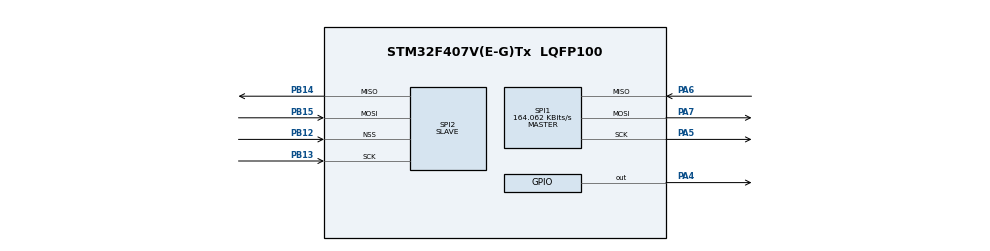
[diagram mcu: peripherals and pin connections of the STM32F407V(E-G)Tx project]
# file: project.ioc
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Mcu.Family=STM32F4
Mcu.Name=STM32F407V(E-G)Tx
Mcu.Package=LQFP100
NVIC.PriorityGroup=NVIC_PRIORITYGROUP_4
NVIC.SPI2_IRQn=true\:0\:0\:false\:false\:true\:true\:true
PA4.GPIO_Speed=GPIO_SPEED_FREQ_VERY_HIGH
PA4.PinState=GPIO_PIN_RESET
PA4.Signal=GPIO_Output
PA5.Mode=Full_Duplex_Master
PA5.Signal=SPI1_SCK
PA6.Mode=Full_Duplex_Master
PA6.Signal=SPI1_MISO
PA7.Mode=Full_Duplex_Master
PA7.Signal=SPI1_MOSI
PB12.Mode=NSS_Signal_Hard_Input
PB12.Signal=SPI2_NSS
PB13.Mode=Full_Duplex_Slave
PB13.Signal=SPI2_SCK
PB14.Mode=Full_Duplex_Slave
PB14.Signal=SPI2_MISO
PB15.Mode=Full_Duplex_Slave
PB15.Signal=SPI2_MOSI
PH0-OSC_IN.Mode=HSE-External-Oscillator
PH0-OSC_IN.Signal=RCC_OSC_IN
PH1-OSC_OUT.Mode=HSE-External-Oscillator
PH1-OSC_OUT.Signal=RCC_OSC_OUT
ProjectManager.HeapSize=0x200
ProjectManager.StackSize=0x400
ProjectManager.TargetToolchain=STM32CubeIDE
RCC.48MHZClocksFreq_Value=42000000
RCC.AHBFreq_Value=168000000
RCC.APB1CLKDivider=RCC_HCLK_DIV4
RCC.APB1Freq_Value=42000000
RCC.APB1TimFreq_Value=84000000
RCC.APB2CLKDivider=RCC_HCLK_DIV4
RCC.APB2Freq_Value=42000000
RCC.APB2TimFreq_Value=84000000
RCC.CortexFreq_Value=168000000
RCC.HCLKFreq_Value=168000000
RCC.HSE_VALUE=8000000
RCC.HSI_VALUE=16000000
RCC.LSE_VALUE=32768
RCC.PLLM=8
RCC.PLLN=336
RCC.PLLQ=8
RCC.PLLSourceVirtual=RCC_PLLSOURCE_HSE
RCC.SYSCLKFreq_VALUE=168000000
RCC.SYSCLKSource=RCC_SYSCLKSOURCE_PLLCLK
RCC.VCOOutputFreq_Value=336000000
SPI1.BaudRatePrescaler=SPI_BAUDRATEPRESCALER_256
SPI1.CRCCalculation=SPI_CRCCALCULATION_DISABLE
SPI1.CalculateBaudRate=164.062 KBits/s
SPI1.Direction=SPI_DIRECTION_2LINES
SPI1.Mode=SPI_MODE_MASTER
SPI1.VirtualType=VM_MASTER
SPI2.CRCCalculation=SPI_CRCCALCULATION_DISABLE
SPI2.Direction=SPI_DIRECTION_2LINES
SPI2.Mode=SPI_MODE_SLAVE
SPI2.VirtualNSS=VM_NSSHARD
SPI2.VirtualType=VM_SLAVE
board=project

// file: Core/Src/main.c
/**
  ******************************************************************************
  * File Name          : main.c
  * Description        : Main program body
  ******************************************************************************
  *
  * COPYRIGHT(c) 2017 STMicroelectronics
  *
  * Redistribution and use in source and binary forms, with or without modification,
  * are permitted provided that the following conditions are met:
  *   1. Redistributions of source code must retain the above copyright notice,
  *      this list of conditions and the following disclaimer.
  *   2. Redistributions in binary form must reproduce the above copyright notice,
  *      this list of conditions and the following disclaimer in the documentation
  *      and/or other materials provided with the distribution.
  *   3. Neither the name of STMicroelectronics nor the names of its contributors
  *      may be used to endorse or promote products derived from this software
  *      without specific prior written permission.
  *
  * THIS SOFTWARE IS PROVIDED BY THE COPYRIGHT HOLDERS AND CONTRIBUTORS "AS IS"
  * AND ANY EXPRESS OR IMPLIED WARRANTIES, INCLUDING, BUT NOT LIMITED TO, THE
  * IMPLIED WARRANTIES OF MERCHANTABILITY AND FITNESS FOR A PARTICULAR PURPOSE ARE
  * DISCLAIMED. IN NO EVENT SHALL THE COPYRIGHT HOLDER OR CONTRIBUTORS BE LIABLE
  * FOR ANY DIRECT, INDIRECT, INCIDENTAL, SPECIAL, EXEMPLARY, OR CONSEQUENTIAL
  * DAMAGES (INCLUDING, BUT NOT LIMITED TO, PROCUREMENT OF SUBSTITUTE GOODS OR
  * SERVICES; LOSS OF USE, DATA, OR PROFITS; OR BUSINESS INTERRUPTION) HOWEVER
  * CAUSED AND ON ANY THEORY OF LIABILITY, WHETHER IN CONTRACT, STRICT LIABILITY,
  * OR TORT (INCLUDING NEGLIGENCE OR OTHERWISE) ARISING IN ANY WAY OUT OF THE USE
  * OF THIS SOFTWARE, EVEN IF ADVISED OF THE POSSIBILITY OF SUCH DAMAGE.
  *
  ******************************************************************************
  */
#include "main.h"
#include "stm32f4xx_hal.h"

#include "DHT.h"
#include <stdio.h>

SPI_HandleTypeDef hspi1;
SPI_HandleTypeDef hspi2;

/* USER CODE BEGIN PV */
/* Private variables ---------------------------------------------------------*/
#define spi_dis HAL_GPIO_WritePin(GPIOA,GPIO_PIN_4,GPIO_PIN_SET)
#define spi_en HAL_GPIO_WritePin(GPIOA,GPIO_PIN_4,GPIO_PIN_RESET)
/* USER CODE END PV */

void SystemClock_Config(void);
void Error_Handler(void);
static void MX_GPIO_Init(void);
static void MX_SPI1_Init(void);
static void MX_SPI2_Init(void);
void Init_OnBoard_LEDs(void);

/* USER CODE BEGIN PFP */
/* Private function prototypes -----------------------------------------------*/

/* USER CODE END PFP */
uint8_t data_send = 0 , data_get;
void HAL_SPI_RxCpltCallback(SPI_HandleTypeDef *hspi);

/* USER CODE END 0 */

DHT_DataTypedef DHT11_Data;
uint8_t Temperature, Humidity;
uint8_t data2[1];
//char uart_buf[50];
//int uart_buf_len;

int main(void)
{

	//spi_dis;
  /* MCU Configuration----------------------------------------------------------*/

  /* Reset of all peripherals, Initializes the Flash interface and the Systick. */
  HAL_Init();

  /* Configure the system clock */
  SystemClock_Config();

  /* Initialize all configured peripherals */
  MX_GPIO_Init();
  MX_SPI1_Init();
  MX_SPI2_Init();

  /* USER CODE BEGIN 2 */
//HAL_SPI_Receive_IT(&hspi1, &data_get, 1);

  /* USER CODE END 2 */

Init_OnBoard_LEDs();

  /* Infinite loop */
  while (1)
  {

	  HAL_Delay(500);
	  DHT_GetData(&DHT11_Data);
	  Temperature = DHT11_Data.Temperature;
	  Humidity = DHT11_Data.Humidity;
	  /*if(Temperature > 10){
		  HAL_GPIO_TogglePin(GPIOD,GPIO_PIN_12|GPIO_PIN_13|GPIO_PIN_14|GPIO_PIN_15);
	  }*/
	  //HAL_GPIO_WritePin(GPIOD,GPIO_PIN_12|GPIO_PIN_13|GPIO_PIN_14|GPIO_PIN_15,GPIO_PIN_RESET);
	  //HAL_GPIO_TogglePin(GPIOD,GPIO_PIN_12|GPIO_PIN_13|GPIO_PIN_14|GPIO_PIN_15);
	  data_send = Temperature;
	  data2[0] = Temperature;
	  //data2[0] = 55;
	  spi_en;
	  HAL_SPI_Receive_IT(&hspi1, &data_get, 1);
	  HAL_GPIO_WritePin(GPIOD,GPIO_PIN_12|GPIO_PIN_13|GPIO_PIN_14|GPIO_PIN_15,GPIO_PIN_SET);
	  HAL_SPI_Transmit(&hspi2, data2, 1, 100000);
	  HAL_GPIO_WritePin(GPIOD,GPIO_PIN_12|GPIO_PIN_13|GPIO_PIN_14|GPIO_PIN_15,GPIO_PIN_RESET);

  }
  /* USER CODE END 3 */
}

void Init_OnBoard_LEDs(void)
{
	 __HAL_RCC_GPIOD_CLK_ENABLE();
	GPIO_InitTypeDef BoardLEDs;
	BoardLEDs.Mode = GPIO_MODE_OUTPUT_PP;
	BoardLEDs.Pin = GPIO_PIN_12|GPIO_PIN_13|GPIO_PIN_14|GPIO_PIN_15;
	HAL_GPIO_Init(GPIOD, &BoardLEDs);
}

/** System Clock Configuration
*/
void SystemClock_Config(void)
{
  RCC_OscInitTypeDef RCC_OscInitStruct = {0};
  RCC_ClkInitTypeDef RCC_ClkInitStruct = {0};

  /** Configure the main internal regulator output voltage
  */
  __HAL_RCC_PWR_CLK_ENABLE();
  __HAL_PWR_VOLTAGESCALING_CONFIG(PWR_REGULATOR_VOLTAGE_SCALE1);
  /** Initializes the RCC Oscillators according to the specified parameters
  * in the RCC_OscInitTypeDef structure.
  */
  RCC_OscInitStruct.OscillatorType = RCC_OSCILLATORTYPE_HSI;
  RCC_OscInitStruct.HSIState = RCC_HSI_ON;
  RCC_OscInitStruct.HSICalibrationValue = RCC_HSICALIBRATION_DEFAULT;
  RCC_OscInitStruct.PLL.PLLState = RCC_PLL_NONE;
  if (HAL_RCC_OscConfig(&RCC_OscInitStruct) != HAL_OK)
  {
    Error_Handler();
  }
  /** Initializes the CPU, AHB and APB buses clocks
  */
  RCC_ClkInitStruct.ClockType = RCC_CLOCKTYPE_HCLK|RCC_CLOCKTYPE_SYSCLK
                              |RCC_CLOCKTYPE_PCLK1|RCC_CLOCKTYPE_PCLK2;
  RCC_ClkInitStruct.SYSCLKSource = RCC_SYSCLKSOURCE_HSI;
  RCC_ClkInitStruct.AHBCLKDivider = RCC_SYSCLK_DIV1;
  RCC_ClkInitStruct.APB1CLKDivider = RCC_HCLK_DIV1;
  RCC_ClkInitStruct.APB2CLKDivider = RCC_HCLK_DIV1;

  if (HAL_RCC_ClockConfig(&RCC_ClkInitStruct, FLASH_LATENCY_0) != HAL_OK)
  {
    Error_Handler();
  }
}

/* SPI1 init function */
static void MX_SPI1_Init(void)
{

  hspi1.Instance = SPI1;
  hspi1.Init.Mode = SPI_MODE_MASTER;
  hspi1.Init.Direction = SPI_DIRECTION_2LINES;
  hspi1.Init.DataSize = SPI_DATASIZE_8BIT;
  hspi1.Init.CLKPolarity = SPI_POLARITY_LOW;
  hspi1.Init.CLKPhase = SPI_PHASE_1EDGE;
  hspi1.Init.NSS = SPI_NSS_SOFT;
  hspi1.Init.BaudRatePrescaler = SPI_BAUDRATEPRESCALER_256;
  hspi1.Init.FirstBit = SPI_FIRSTBIT_MSB;
  hspi1.Init.TIMode = SPI_TIMODE_DISABLE;
  hspi1.Init.CRCCalculation = SPI_CRCCALCULATION_DISABLE;
  hspi1.Init.CRCPolynomial = 10;
  if (HAL_SPI_Init(&hspi1) != HAL_OK)
  {
    Error_Handler();
  }
}

/* SPI2 init function */
static void MX_SPI2_Init(void)
{

  hspi2.Instance = SPI2;
  hspi2.Init.Mode = SPI_MODE_SLAVE;
  hspi2.Init.Direction = SPI_DIRECTION_1LINE;
  hspi2.Init.DataSize = SPI_DATASIZE_8BIT;
  hspi2.Init.CLKPolarity = SPI_POLARITY_LOW;
  hspi2.Init.CLKPhase = SPI_PHASE_1EDGE;
  hspi2.Init.NSS = SPI_NSS_HARD_INPUT;
  hspi2.Init.FirstBit = SPI_FIRSTBIT_MSB;
  hspi2.Init.TIMode = SPI_TIMODE_DISABLE;
  hspi2.Init.CRCCalculation = SPI_CRCCALCULATION_DISABLE;
  hspi2.Init.CRCPolynomial = 10;
  if (HAL_SPI_Init(&hspi2) != HAL_OK)
  {
    Error_Handler();
  }
}

/** Configure pins as
        * Analog
        * Input
        * Output
        * EVENT_OUT
        * EXTI
*/
static void MX_GPIO_Init(void)
{

  GPIO_InitTypeDef GPIO_InitStruct;

  /* GPIO Ports Clock Enable */
  __HAL_RCC_GPIOH_CLK_ENABLE();
  __HAL_RCC_GPIOA_CLK_ENABLE();
  __HAL_RCC_GPIOB_CLK_ENABLE();

  /*Configure GPIO pin Output Level */
  HAL_GPIO_WritePin(GPIOA, GPIO_PIN_4, GPIO_PIN_RESET);

  /*Configure GPIO pin : PA4 */
  GPIO_InitStruct.Pin = GPIO_PIN_4;
  GPIO_InitStruct.Mode = GPIO_MODE_OUTPUT_PP;
  GPIO_InitStruct.Pull = GPIO_NOPULL;
  GPIO_InitStruct.Speed = GPIO_SPEED_FREQ_VERY_HIGH;
  HAL_GPIO_Init(GPIOA, &GPIO_InitStruct);

}

/* USER CODE BEGIN 4 */
void HAL_SPI_RxCpltCallback(SPI_HandleTypeDef *hspi)
{
  if(hspi->Instance == hspi2.Instance)
  {
		spi_dis;
    HAL_SPI_Receive_IT(&hspi2, & data_get, 1);
  }
}
/* USER CODE END 4 */

void Error_Handler(void)
{
  while(1)
  {
  }
}

/************************ (C) COPYRIGHT STMicroelectronics *****END OF FILE****/
